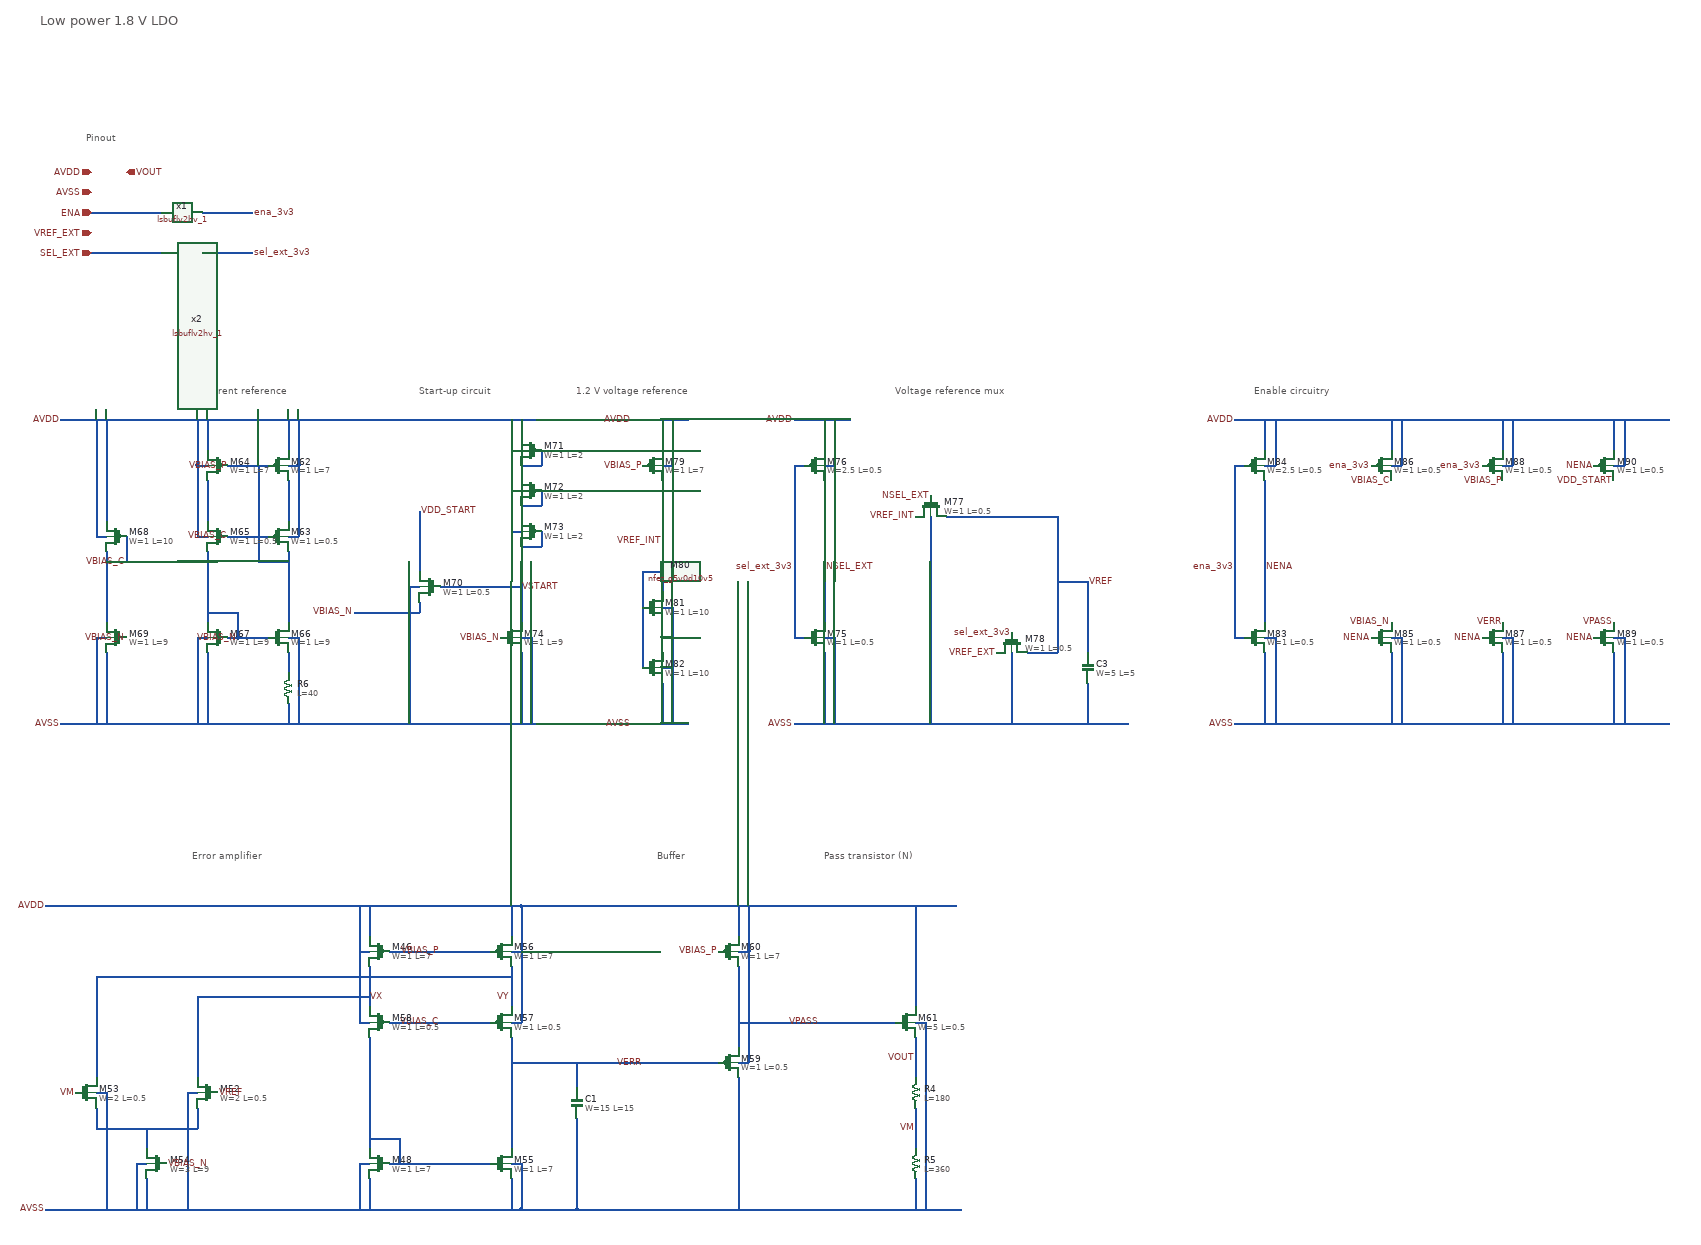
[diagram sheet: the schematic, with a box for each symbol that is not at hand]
v {xschem version=3.4.5 file_version=1.2
}
G {}
K {}
V {}
S {}
E {}
T {Low power 1.8 V LDO} 540 -2520 0 0 0.8 0.8 {}
T {Error amplifier} 840 -870 0 0 0.5 0.5 {}
T {Enable circuitry} 2940 -1790 0 0 0.5 0.5 {}
T {Pinout} 630 -2290 0 0 0.5 0.5 {}
T {Pass transistor (N)} 2090 -870 0 0 0.5 0.5 {}
T {Buffer} 1760 -870 0 0 0.5 0.5 {}
T {1.2 V voltage reference} 1600 -1790 0 0 0.5 0.5 {}
T {Current reference} 860 -1790 0 0 0.5 0.5 {}
T {Start-up circuit} 1290 -1790 0 0 0.5 0.5 {}
T {Voltage reference mux} 2230 -1790 0 0 0.5 0.5 {}
N 1190 -220 1190 -160 {
lab=AVSS}
N 1170 -530 1190 -530 {
lab=AVDD}
N 1170 -250 1190 -250 {
lab=AVSS}
N 650 -360 650 -320 {
lab=#net1}
N 650 -320 850 -320 {
lab=#net1}
N 850 -360 850 -320 {
lab=#net1}
N 750 -320 750 -280 {
lab=#net1}
N 750 -220 750 -160 {
lab=AVSS}
N 730 -250 750 -250 {
lab=AVSS}
N 730 -250 730 -160 {
lab=AVSS}
N 830 -390 850 -390 {
lab=AVSS}
N 830 -390 830 -160 {
lab=AVSS}
N 650 -390 670 -390 {
lab=AVSS}
N 670 -390 670 -160 {
lab=AVSS}
N 1190 -640 1190 -560 {
lab=VX}
N 1190 -760 1190 -700 {
lab=AVDD}
N 1170 -670 1190 -670 {
lab=AVDD}
N 1170 -760 1170 -530 {
lab=AVDD}
N 1470 -220 1470 -160 {
lab=AVSS}
N 1470 -530 1490 -530 {
lab=AVDD}
N 1470 -250 1490 -250 {
lab=AVSS}
N 1470 -640 1470 -560 {
lab=VY}
N 1470 -760 1470 -700 {
lab=AVDD}
N 1470 -670 1490 -670 {
lab=AVDD}
N 1490 -760 1490 -530 {
lab=AVDD}
N 1230 -670 1430 -670 {
lab=VBIAS_P}
N 1230 -530 1430 -530 {
lab=VBIAS_C}
N 1230 -250 1430 -250 {
lab=#net2}
N 1250 -300 1250 -250 {
lab=#net2}
N 1190 -300 1250 -300 {
lab=#net2}
N 850 -580 850 -420 {
lab=VX}
N 850 -580 1190 -580 {
lab=VX}
N 650 -620 650 -420 {
lab=VY}
N 650 -620 1470 -620 {
lab=VY}
N 550 -160 1490 -160 {
lab=AVSS}
N 550 -760 1490 -760 {
lab=AVDD}
N 1190 -500 1190 -280 {
lab=#net2}
N 1470 -500 1470 -280 {
lab=VERR}
N 1490 -250 1490 -160 {
lab=AVSS}
N 1170 -250 1170 -160 {
lab=AVSS}
N 1920 -640 1920 -480 {
lab=VPASS}
N 2270 -500 2270 -420 {
lab=VOUT}
N 2270 -360 2270 -280 {
lab=VM}
N 2270 -220 2270 -160 {
lab=AVSS}
N 2270 -530 2290 -530 {
lab=AVSS}
N 2290 -530 2290 -160 {
lab=AVSS}
N 1600 -340 1600 -160 {
lab=AVSS}
N 1490 -160 1600 -160 {
lab=AVSS}
N 580 -1120 1520 -1120 {
lab=AVSS}
N 580 -1720 1520 -1720 {
lab=AVDD}
N 1030 -1720 1030 -1660 {
lab=AVDD}
N 1030 -1630 1050 -1630 {
lab=AVDD}
N 1050 -1720 1050 -1630 {
lab=AVDD}
N 1030 -1600 1030 -1520 {
lab=#net3}
N 870 -1720 870 -1660 {
lab=AVDD}
N 850 -1630 870 -1630 {
lab=AVDD}
N 850 -1720 850 -1630 {
lab=AVDD}
N 870 -1600 870 -1520 {
lab=#net4}
N 910 -1630 990 -1630 {
lab=VBIAS_P}
N 910 -1490 990 -1490 {
lab=VBIAS_C}
N 1030 -1490 1050 -1490 {
lab=AVDD}
N 1050 -1630 1050 -1490 {
lab=AVDD}
N 850 -1490 870 -1490 {
lab=AVDD}
N 850 -1630 850 -1490 {
lab=AVDD}
N 1030 -1260 1030 -1220 {
lab=#net5}
N 870 -1260 870 -1120 {
lab=AVSS}
N 1030 -1290 1050 -1290 {
lab=AVSS}
N 1050 -1290 1050 -1120 {
lab=AVSS}
N 850 -1290 870 -1290 {
lab=AVSS}
N 850 -1290 850 -1120 {
lab=AVSS}
N 970 -1630 970 -1440 {
lab=VBIAS_P}
N 970 -1440 1030 -1440 {
lab=VBIAS_P}
N 930 -1340 930 -1290 {
lab=VBIAS_N}
N 870 -1340 930 -1340 {
lab=VBIAS_N}
N 650 -1490 670 -1490 {
lab=AVDD}
N 670 -1460 670 -1320 {
lab=VBIAS_C}
N 650 -1720 650 -1490 {
lab=AVDD}
N 670 -1260 670 -1120 {
lab=AVSS}
N 650 -1290 670 -1290 {
lab=AVSS}
N 650 -1290 650 -1120 {
lab=AVSS}
N 670 -1720 670 -1520 {
lab=AVDD}
N 710 -1490 710 -1440 {
lab=VBIAS_C}
N 670 -1440 710 -1440 {
lab=VBIAS_C}
N 870 -1460 870 -1320 {
lab=VBIAS_N}
N 1030 -1460 1030 -1320 {
lab=VBIAS_P}
N 910 -1290 930 -1290 {
lab=VBIAS_N}
N 1290 -1360 1290 -1340 {
lab=VBIAS_N}
N 1270 -1390 1290 -1390 {
lab=AVSS}
N 1270 -1390 1270 -1120 {
lab=AVSS}
N 1490 -1470 1490 -1320 {
lab=VSTART}
N 1490 -1550 1490 -1530 {
lab=#net6}
N 1490 -1630 1490 -1610 {
lab=#net7}
N 1490 -1720 1490 -1690 {
lab=AVDD}
N 1470 -1500 1490 -1500 {
lab=AVDD}
N 1470 -1720 1470 -1500 {
lab=AVDD}
N 1470 -1660 1500 -1660 {
lab=AVDD}
N 1470 -1580 1490 -1580 {
lab=AVDD}
N 1490 -1470 1530 -1470 {
lab=VSTART}
N 1530 -1500 1530 -1470 {
lab=VSTART}
N 1490 -1550 1530 -1550 {
lab=#net6}
N 1530 -1580 1530 -1550 {
lab=#net6}
N 1490 -1630 1530 -1630 {
lab=#net7}
N 1530 -1660 1530 -1630 {
lab=#net7}
N 1330 -1390 1490 -1390 {
lab=VSTART}
N 1490 -1290 1510 -1290 {
lab=AVSS}
N 1510 -1290 1510 -1120 {
lab=AVSS}
N 2090 -1600 2090 -1320 {
lab=NSEL_EXT}
N 2030 -1630 2050 -1630 {
lab=sel_ext_3v3}
N 2030 -1630 2030 -1290 {
lab=sel_ext_3v3}
N 2030 -1290 2050 -1290 {
lab=sel_ext_3v3}
N 2090 -1260 2090 -1120 {
lab=AVSS}
N 2090 -1720 2090 -1660 {
lab=AVDD}
N 2090 -1630 2110 -1630 {
lab=AVDD}
N 2110 -1720 2110 -1630 {
lab=AVDD}
N 2090 -1290 2110 -1290 {
lab=AVSS}
N 2110 -1290 2110 -1120 {
lab=AVSS}
N 2030 -1720 2140 -1720 {
lab=AVDD}
N 2030 -1120 2130 -1120 {
lab=AVSS}
N 2330 -1530 2550 -1530 {
lab=VREF}
N 2550 -1530 2550 -1260 {
lab=VREF}
N 2490 -1260 2550 -1260 {
lab=VREF}
N 2610 -1400 2610 -1260 {
lab=VREF}
N 2550 -1400 2610 -1400 {
lab=VREF}
N 1490 -760 2350 -760 {
lab=AVDD}
N 1920 -760 1920 -700 {
lab=AVDD}
N 1920 -670 1940 -670 {
lab=AVDD}
N 1940 -760 1940 -670 {
lab=AVDD}
N 1920 -450 1940 -450 {
lab=AVDD}
N 1940 -670 1940 -450 {
lab=AVDD}
N 2270 -760 2270 -560 {
lab=AVDD}
N 1920 -530 2230 -530 {
lab=VPASS}
N 1600 -160 2360 -160 {
lab=AVSS}
N 1920 -420 1920 -160 {
lab=AVSS}
N 1470 -450 1880 -450 {
lab=VERR}
N 1600 -450 1600 -400 {
lab=VERR}
N 2130 -1120 2690 -1120 {
lab=AVSS}
N 2610 -1200 2610 -1120 {
lab=AVSS}
N 2460 -1260 2460 -1120 {
lab=AVSS}
N 2300 -1530 2300 -1120 {
lab=AVSS}
N 930 -1290 990 -1290 {
lab=VBIAS_N}
N 1030 -1160 1030 -1120 {
lab=AVSS}
N 1490 -1260 1490 -1120 {
lab=AVSS}
N 1160 -1340 1290 -1340 {
lab=VBIAS_N}
N 1770 -1200 1770 -1120 {
lab=AVSS}
N 1770 -1350 1790 -1350 {
lab=AVSS}
N 1790 -1350 1790 -1120 {
lab=AVSS}
N 1770 -1290 1790 -1290 {
lab=AVSS}
N 1770 -1230 1790 -1230 {
lab=AVSS}
N 1730 -1420 1730 -1230 {
lab=VREF_INT}
N 1730 -1420 1770 -1420 {
lab=VREF_INT}
N 1770 -1600 1770 -1380 {
lab=VREF_INT}
N 1770 -1630 1790 -1630 {
lab=AVDD}
N 1790 -1720 1790 -1630 {
lab=AVDD}
N 1770 -1720 1770 -1660 {
lab=AVDD}
N 1710 -1720 1820 -1720 {
lab=AVDD}
N 1710 -1120 1820 -1120 {
lab=AVSS}
N 2960 -1600 2960 -1320 {
lab=NENA}
N 2900 -1630 2920 -1630 {
lab=ena_3v3}
N 2900 -1630 2900 -1290 {
lab=ena_3v3}
N 2900 -1290 2920 -1290 {
lab=ena_3v3}
N 2960 -1260 2960 -1120 {
lab=AVSS}
N 2960 -1720 2960 -1660 {
lab=AVDD}
N 2960 -1630 2980 -1630 {
lab=AVDD}
N 2980 -1720 2980 -1630 {
lab=AVDD}
N 2960 -1290 2980 -1290 {
lab=AVSS}
N 2980 -1290 2980 -1120 {
lab=AVSS}
N 2900 -1720 3010 -1720 {
lab=AVDD}
N 3210 -1720 3210 -1660 {
lab=AVDD}
N 3210 -1630 3230 -1630 {
lab=AVDD}
N 3230 -1720 3230 -1630 {
lab=AVDD}
N 3210 -1260 3210 -1120 {
lab=AVSS}
N 3210 -1290 3230 -1290 {
lab=AVSS}
N 3230 -1290 3230 -1120 {
lab=AVSS}
N 3430 -1720 3430 -1660 {
lab=AVDD}
N 3430 -1630 3450 -1630 {
lab=AVDD}
N 3450 -1720 3450 -1630 {
lab=AVDD}
N 3430 -1260 3430 -1120 {
lab=AVSS}
N 3430 -1290 3450 -1290 {
lab=AVSS}
N 3450 -1290 3450 -1120 {
lab=AVSS}
N 3650 -1720 3650 -1660 {
lab=AVDD}
N 3650 -1630 3670 -1630 {
lab=AVDD}
N 3670 -1720 3670 -1630 {
lab=AVDD}
N 3650 -1260 3650 -1120 {
lab=AVSS}
N 3650 -1290 3670 -1290 {
lab=AVSS}
N 3670 -1290 3670 -1120 {
lab=AVSS}
N 1290 -1540 1290 -1420 {
lab=VDD_START}
N 3010 -1720 3760 -1720 {
lab=AVDD}
N 3010 -1120 3760 -1120 {
lab=AVSS}
N 2900 -1120 3010 -1120 {
lab=AVSS}
N 640 -2130 780 -2130 {
lab=ENA}
N 640 -2050 780 -2050 {
lab=SEL_EXT}
N 860 -2130 960 -2130 {
lab=ena_3v3}
N 860 -2050 960 -2050 {
lab=sel_ext_3v3}
C {devices/ipin.sym} 640 -2130 0 0 {name=p49 lab=ENA}
C {devices/ipin.sym} 640 -2210 0 0 {name=p35 lab=AVDD}
C {devices/ipin.sym} 640 -2170 0 0 {name=p36 lab=AVSS}
C {devices/opin.sym} 710 -2210 0 0 {name=p39 lab=VOUT}
C {devices/ipin.sym} 640 -2050 0 0 {name=p72 lab=SEL_EXT}
C {devices/ipin.sym} 640 -2090 0 0 {name=p73 lab=VREF_EXT}
C {sky130_fd_pr/pfet_g5v0d10v5.sym} 1210 -670 0 1 {name=M46
W=1
L=7
nf=1
mult=1
ad="'int((nf+1)/2) * W/nf * 0.29'" 
pd="'2*int((nf+1)/2) * (W/nf + 0.29)'"
as="'int((nf+2)/2) * W/nf * 0.29'" 
ps="'2*int((nf+2)/2) * (W/nf + 0.29)'"
nrd="'0.29 / W'" nrs="'0.29 / W'"
sa=0 sb=0 sd=0
model=pfet_g5v0d10v5
spiceprefix=X
}
C {sky130_fd_pr/nfet_g5v0d10v5.sym} 1210 -250 0 1 {name=M48
W=1
L=7
nf=1
mult=1
ad="'int((nf+1)/2) * W/nf * 0.29'" 
pd="'2*int((nf+1)/2) * (W/nf + 0.29)'"
as="'int((nf+2)/2) * W/nf * 0.29'" 
ps="'2*int((nf+2)/2) * (W/nf + 0.29)'"
nrd="'0.29 / W'" nrs="'0.29 / W'"
sa=0 sb=0 sd=0
model=nfet_g5v0d10v5
spiceprefix=X
}
C {devices/lab_pin.sym} 550 -760 0 0 {name=p3 sig_type=std_logic lab=AVDD}
C {devices/lab_pin.sym} 550 -160 0 0 {name=p4 sig_type=std_logic lab=AVSS}
C {sky130_fd_pr/nfet_g5v0d10v5.sym} 870 -390 0 1 {name=M52
W=2
L=0.5
nf=1
mult=1
ad="'int((nf+1)/2) * W/nf * 0.29'" 
pd="'2*int((nf+1)/2) * (W/nf + 0.29)'"
as="'int((nf+2)/2) * W/nf * 0.29'" 
ps="'2*int((nf+2)/2) * (W/nf + 0.29)'"
nrd="'0.29 / W'" nrs="'0.29 / W'"
sa=0 sb=0 sd=0
model=nfet_g5v0d10v5
spiceprefix=X
}
C {sky130_fd_pr/nfet_g5v0d10v5.sym} 630 -390 0 0 {name=M53
W=2
L=0.5
nf=1
mult=1
ad="'int((nf+1)/2) * W/nf * 0.29'" 
pd="'2*int((nf+1)/2) * (W/nf + 0.29)'"
as="'int((nf+2)/2) * W/nf * 0.29'" 
ps="'2*int((nf+2)/2) * (W/nf + 0.29)'"
nrd="'0.29 / W'" nrs="'0.29 / W'"
sa=0 sb=0 sd=0
model=nfet_g5v0d10v5
spiceprefix=X
}
C {sky130_fd_pr/nfet_g5v0d10v5.sym} 770 -250 0 1 {name=M54
W=3
L=9
nf=1
mult=1
ad="'int((nf+1)/2) * W/nf * 0.29'" 
pd="'2*int((nf+1)/2) * (W/nf + 0.29)'"
as="'int((nf+2)/2) * W/nf * 0.29'" 
ps="'2*int((nf+2)/2) * (W/nf + 0.29)'"
nrd="'0.29 / W'" nrs="'0.29 / W'"
sa=0 sb=0 sd=0
model=nfet_g5v0d10v5
spiceprefix=X
}
C {sky130_fd_pr/nfet_g5v0d10v5.sym} 1450 -250 0 0 {name=M55
W=1
L=7
nf=1
mult=1
ad="'int((nf+1)/2) * W/nf * 0.29'" 
pd="'2*int((nf+1)/2) * (W/nf + 0.29)'"
as="'int((nf+2)/2) * W/nf * 0.29'" 
ps="'2*int((nf+2)/2) * (W/nf + 0.29)'"
nrd="'0.29 / W'" nrs="'0.29 / W'"
sa=0 sb=0 sd=0
model=nfet_g5v0d10v5
spiceprefix=X
}
C {devices/lab_pin.sym} 610 -390 2 1 {name=p1 sig_type=std_logic lab=VM}
C {devices/lab_pin.sym} 890 -390 2 0 {name=p6 sig_type=std_logic lab=VREF}
C {devices/lab_pin.sym} 790 -250 2 0 {name=p2 sig_type=std_logic lab=VBIAS_N}
C {devices/lab_pin.sym} 1330 -670 3 0 {name=p10 sig_type=std_logic lab=VBIAS_P}
C {devices/lab_pin.sym} 1330 -530 3 0 {name=p11 sig_type=std_logic lab=VBIAS_C}
C {sky130_fd_pr/pfet_g5v0d10v5.sym} 1450 -670 0 0 {name=M56
W=1
L=7
nf=1
mult=1
ad="'int((nf+1)/2) * W/nf * 0.29'" 
pd="'2*int((nf+1)/2) * (W/nf + 0.29)'"
as="'int((nf+2)/2) * W/nf * 0.29'" 
ps="'2*int((nf+2)/2) * (W/nf + 0.29)'"
nrd="'0.29 / W'" nrs="'0.29 / W'"
sa=0 sb=0 sd=0
model=pfet_g5v0d10v5
spiceprefix=X
}
C {sky130_fd_pr/pfet_g5v0d10v5.sym} 1450 -530 0 0 {name=M57
W=1
L=0.5
nf=1
mult=1
ad="'int((nf+1)/2) * W/nf * 0.29'" 
pd="'2*int((nf+1)/2) * (W/nf + 0.29)'"
as="'int((nf+2)/2) * W/nf * 0.29'" 
ps="'2*int((nf+2)/2) * (W/nf + 0.29)'"
nrd="'0.29 / W'" nrs="'0.29 / W'"
sa=0 sb=0 sd=0
model=pfet_g5v0d10v5
spiceprefix=X
}
C {sky130_fd_pr/pfet_g5v0d10v5.sym} 1210 -530 0 1 {name=M58
W=1
L=0.5
nf=1
mult=1
ad="'int((nf+1)/2) * W/nf * 0.29'" 
pd="'2*int((nf+1)/2) * (W/nf + 0.29)'"
as="'int((nf+2)/2) * W/nf * 0.29'" 
ps="'2*int((nf+2)/2) * (W/nf + 0.29)'"
nrd="'0.29 / W'" nrs="'0.29 / W'"
sa=0 sb=0 sd=0
model=pfet_g5v0d10v5
spiceprefix=X
}
C {devices/lab_pin.sym} 1190 -580 2 0 {name=p12 sig_type=std_logic lab=VX}
C {devices/lab_pin.sym} 1470 -580 2 1 {name=p15 sig_type=std_logic lab=VY}
C {sky130_fd_pr/pfet_g5v0d10v5.sym} 1900 -450 0 0 {name=M59
W=1
L=0.5
nf=1
mult=1
ad="'int((nf+1)/2) * W/nf * 0.29'" 
pd="'2*int((nf+1)/2) * (W/nf + 0.29)'"
as="'int((nf+2)/2) * W/nf * 0.29'" 
ps="'2*int((nf+2)/2) * (W/nf + 0.29)'"
nrd="'0.29 / W'" nrs="'0.29 / W'"
sa=0 sb=0 sd=0
model=pfet_g5v0d10v5
spiceprefix=X
}
C {devices/lab_pin.sym} 1730 -450 3 0 {name=p16 sig_type=std_logic lab=VERR}
C {sky130_fd_pr/pfet_g5v0d10v5.sym} 1900 -670 0 0 {name=M60
W=1
L=7
nf=1
mult=1
ad="'int((nf+1)/2) * W/nf * 0.29'" 
pd="'2*int((nf+1)/2) * (W/nf + 0.29)'"
as="'int((nf+2)/2) * W/nf * 0.29'" 
ps="'2*int((nf+2)/2) * (W/nf + 0.29)'"
nrd="'0.29 / W'" nrs="'0.29 / W'"
sa=0 sb=0 sd=0
model=pfet_g5v0d10v5
spiceprefix=X
}
C {sky130_fd_pr/res_xhigh_po_0p35.sym} 2270 -390 0 1 {name=R4
L=180
model=res_xhigh_po_0p35
spiceprefix=X
mult=1}
C {sky130_fd_pr/res_xhigh_po_0p35.sym} 2270 -250 0 1 {name=R5
L=360
model=res_xhigh_po_0p35
spiceprefix=X
mult=1}
C {devices/lab_pin.sym} 2270 -320 0 0 {name=p17 sig_type=std_logic lab=VM}
C {devices/lab_pin.sym} 2270 -460 0 0 {name=p20 sig_type=std_logic lab=VOUT}
C {sky130_fd_pr/nfet_g5v0d10v5.sym} 2250 -530 0 0 {name=M61
W=5
L=0.5
nf=1
mult=1000
ad="'int((nf+1)/2) * W/nf * 0.29'" 
pd="'2*int((nf+1)/2) * (W/nf + 0.29)'"
as="'int((nf+2)/2) * W/nf * 0.29'" 
ps="'2*int((nf+2)/2) * (W/nf + 0.29)'"
nrd="'0.29 / W'" nrs="'0.29 / W'"
sa=0 sb=0 sd=0
model=nfet_g5v0d10v5
spiceprefix=X
}
C {sky130_fd_pr/cap_mim_m3_1.sym} 1600 -370 0 0 {name=C1 model=cap_mim_m3_1 W=15 L=15 MF=3 spiceprefix=X}
C {devices/lab_pin.sym} 580 -1120 0 0 {name=p21 sig_type=std_logic lab=AVSS}
C {devices/lab_pin.sym} 580 -1720 0 0 {name=p59 sig_type=std_logic lab=AVDD}
C {sky130_fd_pr/pfet_g5v0d10v5.sym} 1010 -1630 0 0 {name=M62
W=1
L=7
nf=1
mult=1
ad="'int((nf+1)/2) * W/nf * 0.29'" 
pd="'2*int((nf+1)/2) * (W/nf + 0.29)'"
as="'int((nf+2)/2) * W/nf * 0.29'" 
ps="'2*int((nf+2)/2) * (W/nf + 0.29)'"
nrd="'0.29 / W'" nrs="'0.29 / W'"
sa=0 sb=0 sd=0
model=pfet_g5v0d10v5
spiceprefix=X
}
C {sky130_fd_pr/pfet_g5v0d10v5.sym} 1010 -1490 0 0 {name=M63
W=1
L=0.5
nf=1
mult=1
ad="'int((nf+1)/2) * W/nf * 0.29'" 
pd="'2*int((nf+1)/2) * (W/nf + 0.29)'"
as="'int((nf+2)/2) * W/nf * 0.29'" 
ps="'2*int((nf+2)/2) * (W/nf + 0.29)'"
nrd="'0.29 / W'" nrs="'0.29 / W'"
sa=0 sb=0 sd=0
model=pfet_g5v0d10v5
spiceprefix=X
}
C {sky130_fd_pr/pfet_g5v0d10v5.sym} 890 -1630 0 1 {name=M64
W=1
L=7
nf=1
mult=1
ad="'int((nf+1)/2) * W/nf * 0.29'" 
pd="'2*int((nf+1)/2) * (W/nf + 0.29)'"
as="'int((nf+2)/2) * W/nf * 0.29'" 
ps="'2*int((nf+2)/2) * (W/nf + 0.29)'"
nrd="'0.29 / W'" nrs="'0.29 / W'"
sa=0 sb=0 sd=0
model=pfet_g5v0d10v5
spiceprefix=X
}
C {sky130_fd_pr/pfet_g5v0d10v5.sym} 890 -1490 0 1 {name=M65
W=1
L=0.5
nf=1
mult=1
ad="'int((nf+1)/2) * W/nf * 0.29'" 
pd="'2*int((nf+1)/2) * (W/nf + 0.29)'"
as="'int((nf+2)/2) * W/nf * 0.29'" 
ps="'2*int((nf+2)/2) * (W/nf + 0.29)'"
nrd="'0.29 / W'" nrs="'0.29 / W'"
sa=0 sb=0 sd=0
model=pfet_g5v0d10v5
spiceprefix=X
}
C {sky130_fd_pr/nfet_g5v0d10v5.sym} 1010 -1290 0 0 {name=M66
W=1
L=9
nf=1
mult=20
ad="'int((nf+1)/2) * W/nf * 0.29'" 
pd="'2*int((nf+1)/2) * (W/nf + 0.29)'"
as="'int((nf+2)/2) * W/nf * 0.29'" 
ps="'2*int((nf+2)/2) * (W/nf + 0.29)'"
nrd="'0.29 / W'" nrs="'0.29 / W'"
sa=0 sb=0 sd=0
model=nfet_g5v0d10v5
spiceprefix=X
}
C {sky130_fd_pr/nfet_g5v0d10v5.sym} 890 -1290 0 1 {name=M67
W=1
L=9
nf=1
mult=5
ad="'int((nf+1)/2) * W/nf * 0.29'" 
pd="'2*int((nf+1)/2) * (W/nf + 0.29)'"
as="'int((nf+2)/2) * W/nf * 0.29'" 
ps="'2*int((nf+2)/2) * (W/nf + 0.29)'"
nrd="'0.29 / W'" nrs="'0.29 / W'"
sa=0 sb=0 sd=0
model=nfet_g5v0d10v5
spiceprefix=X
}
C {sky130_fd_pr/pfet_g5v0d10v5.sym} 690 -1490 0 1 {name=M68
W=1
L=10
nf=1
mult=1
ad="'int((nf+1)/2) * W/nf * 0.29'" 
pd="'2*int((nf+1)/2) * (W/nf + 0.29)'"
as="'int((nf+2)/2) * W/nf * 0.29'" 
ps="'2*int((nf+2)/2) * (W/nf + 0.29)'"
nrd="'0.29 / W'" nrs="'0.29 / W'"
sa=0 sb=0 sd=0
model=pfet_g5v0d10v5
spiceprefix=X
}
C {sky130_fd_pr/nfet_g5v0d10v5.sym} 690 -1290 0 1 {name=M69
W=1
L=9
nf=1
mult=5
ad="'int((nf+1)/2) * W/nf * 0.29'" 
pd="'2*int((nf+1)/2) * (W/nf + 0.29)'"
as="'int((nf+2)/2) * W/nf * 0.29'" 
ps="'2*int((nf+2)/2) * (W/nf + 0.29)'"
nrd="'0.29 / W'" nrs="'0.29 / W'"
sa=0 sb=0 sd=0
model=nfet_g5v0d10v5
spiceprefix=X
}
C {devices/lab_pin.sym} 710 -1440 3 0 {name=p78 sig_type=std_logic lab=VBIAS_C}
C {devices/lab_pin.sym} 910 -1490 1 1 {name=p79 sig_type=std_logic lab=VBIAS_C}
C {devices/lab_pin.sym} 910 -1630 1 1 {name=p80 sig_type=std_logic lab=VBIAS_P}
C {devices/lab_pin.sym} 930 -1290 3 0 {name=p81 sig_type=std_logic lab=VBIAS_N}
C {sky130_fd_pr/nfet_g5v0d10v5.sym} 1310 -1390 0 1 {name=M70
W=1
L=0.5
nf=1
mult=1
ad="'int((nf+1)/2) * W/nf * 0.29'" 
pd="'2*int((nf+1)/2) * (W/nf + 0.29)'"
as="'int((nf+2)/2) * W/nf * 0.29'" 
ps="'2*int((nf+2)/2) * (W/nf + 0.29)'"
nrd="'0.29 / W'" nrs="'0.29 / W'"
sa=0 sb=0 sd=0
model=nfet_g5v0d10v5
spiceprefix=X
}
C {sky130_fd_pr/pfet_g5v0d10v5.sym} 1510 -1660 0 1 {name=M71
W=1
L=2
nf=1
mult=1
ad="'int((nf+1)/2) * W/nf * 0.29'" 
pd="'2*int((nf+1)/2) * (W/nf + 0.29)'"
as="'int((nf+2)/2) * W/nf * 0.29'" 
ps="'2*int((nf+2)/2) * (W/nf + 0.29)'"
nrd="'0.29 / W'" nrs="'0.29 / W'"
sa=0 sb=0 sd=0
model=pfet_g5v0d10v5
spiceprefix=X
}
C {sky130_fd_pr/pfet_g5v0d10v5.sym} 1510 -1580 0 1 {name=M72
W=1
L=2
nf=1
mult=1
ad="'int((nf+1)/2) * W/nf * 0.29'" 
pd="'2*int((nf+1)/2) * (W/nf + 0.29)'"
as="'int((nf+2)/2) * W/nf * 0.29'" 
ps="'2*int((nf+2)/2) * (W/nf + 0.29)'"
nrd="'0.29 / W'" nrs="'0.29 / W'"
sa=0 sb=0 sd=0
model=pfet_g5v0d10v5
spiceprefix=X
}
C {sky130_fd_pr/pfet_g5v0d10v5.sym} 1510 -1500 0 1 {name=M73
W=1
L=2
nf=1
mult=1
ad="'int((nf+1)/2) * W/nf * 0.29'" 
pd="'2*int((nf+1)/2) * (W/nf + 0.29)'"
as="'int((nf+2)/2) * W/nf * 0.29'" 
ps="'2*int((nf+2)/2) * (W/nf + 0.29)'"
nrd="'0.29 / W'" nrs="'0.29 / W'"
sa=0 sb=0 sd=0
model=pfet_g5v0d10v5
spiceprefix=X
}
C {sky130_fd_pr/nfet_g5v0d10v5.sym} 1470 -1290 0 0 {name=M74
W=1
L=9
nf=1
mult=5
ad="'int((nf+1)/2) * W/nf * 0.29'" 
pd="'2*int((nf+1)/2) * (W/nf + 0.29)'"
as="'int((nf+2)/2) * W/nf * 0.29'" 
ps="'2*int((nf+2)/2) * (W/nf + 0.29)'"
nrd="'0.29 / W'" nrs="'0.29 / W'"
sa=0 sb=0 sd=0
model=nfet_g5v0d10v5
spiceprefix=X
}
C {devices/lab_pin.sym} 1490 -1390 2 0 {name=p82 sig_type=std_logic lab=VSTART}
C {sky130_fd_pr/nfet_g5v0d10v5.sym} 2070 -1290 0 0 {name=M75
W=1
L=0.5
nf=1
mult=1
ad="'int((nf+1)/2) * W/nf * 0.29'" 
pd="'2*int((nf+1)/2) * (W/nf + 0.29)'"
as="'int((nf+2)/2) * W/nf * 0.29'" 
ps="'2*int((nf+2)/2) * (W/nf + 0.29)'"
nrd="'0.29 / W'" nrs="'0.29 / W'"
sa=0 sb=0 sd=0
model=nfet_g5v0d10v5
spiceprefix=X
}
C {sky130_fd_pr/pfet_g5v0d10v5.sym} 2070 -1630 0 0 {name=M76
W=2.5
L=0.5
nf=1
mult=1
ad="'int((nf+1)/2) * W/nf * 0.29'" 
pd="'2*int((nf+1)/2) * (W/nf + 0.29)'"
as="'int((nf+2)/2) * W/nf * 0.29'" 
ps="'2*int((nf+2)/2) * (W/nf + 0.29)'"
nrd="'0.29 / W'" nrs="'0.29 / W'"
sa=0 sb=0 sd=0
model=pfet_g5v0d10v5
spiceprefix=X
}
C {devices/lab_pin.sym} 2030 -1720 0 0 {name=p83 sig_type=std_logic lab=AVDD}
C {devices/lab_pin.sym} 2030 -1120 0 0 {name=p84 sig_type=std_logic lab=AVSS}
C {devices/lab_pin.sym} 2030 -1430 0 0 {name=p85 sig_type=std_logic lab=sel_ext_3v3}
C {devices/lab_pin.sym} 2090 -1430 0 1 {name=p86 sig_type=std_logic lab=NSEL_EXT}
C {sky130_fd_pr/nfet_g5v0d10v5.sym} 2300 -1550 1 0 {name=M77
W=1
L=0.5
nf=1
mult=1
ad="'int((nf+1)/2) * W/nf * 0.29'" 
pd="'2*int((nf+1)/2) * (W/nf + 0.29)'"
as="'int((nf+2)/2) * W/nf * 0.29'" 
ps="'2*int((nf+2)/2) * (W/nf + 0.29)'"
nrd="'0.29 / W'" nrs="'0.29 / W'"
sa=0 sb=0 sd=0
model=nfet_g5v0d10v5
spiceprefix=X
}
C {sky130_fd_pr/nfet_g5v0d10v5.sym} 2460 -1280 1 0 {name=M78
W=1
L=0.5
nf=1
mult=1
ad="'int((nf+1)/2) * W/nf * 0.29'" 
pd="'2*int((nf+1)/2) * (W/nf + 0.29)'"
as="'int((nf+2)/2) * W/nf * 0.29'" 
ps="'2*int((nf+2)/2) * (W/nf + 0.29)'"
nrd="'0.29 / W'" nrs="'0.29 / W'"
sa=0 sb=0 sd=0
model=nfet_g5v0d10v5
spiceprefix=X
}
C {devices/lab_pin.sym} 2460 -1300 0 0 {name=p87 sig_type=std_logic lab=sel_ext_3v3}
C {devices/lab_pin.sym} 2270 -1530 0 0 {name=p88 sig_type=std_logic lab=VREF_INT}
C {devices/lab_pin.sym} 2430 -1260 0 0 {name=p89 sig_type=std_logic lab=VREF_EXT}
C {devices/lab_pin.sym} 2610 -1400 0 1 {name=p90 sig_type=std_logic lab=VREF}
C {devices/lab_pin.sym} 2300 -1570 0 0 {name=p91 sig_type=std_logic lab=NSEL_EXT}
C {sky130_fd_pr/cap_mim_m3_1.sym} 2610 -1230 0 0 {name=C3 model=cap_mim_m3_1 W=5 L=5 MF=1 spiceprefix=X}
C {devices/lab_pin.sym} 2080 -530 3 0 {name=p92 sig_type=std_logic lab=VPASS}
C {devices/lab_pin.sym} 710 -1290 3 0 {name=p93 sig_type=std_logic lab=VBIAS_N}
C {devices/lab_pin.sym} 1450 -1290 3 0 {name=p94 sig_type=std_logic lab=VBIAS_N}
C {devices/lab_pin.sym} 1880 -670 3 0 {name=p95 sig_type=std_logic lab=VBIAS_P}
C {sky130_fd_pr/res_xhigh_po_0p35.sym} 1030 -1190 0 1 {name=R6
L=40
model=res_xhigh_po_0p35
spiceprefix=X
mult=1}
C {devices/lab_pin.sym} 1160 -1340 3 0 {name=p96 sig_type=std_logic lab=VBIAS_N}
C {sky130_fd_pr/pfet_g5v0d10v5.sym} 1750 -1630 0 0 {name=M79
W=1
L=7
nf=1
mult=1
ad="'int((nf+1)/2) * W/nf * 0.29'" 
pd="'2*int((nf+1)/2) * (W/nf + 0.29)'"
as="'int((nf+2)/2) * W/nf * 0.29'" 
ps="'2*int((nf+2)/2) * (W/nf + 0.29)'"
nrd="'0.29 / W'" nrs="'0.29 / W'"
sa=0 sb=0 sd=0
model=pfet_g5v0d10v5
spiceprefix=X
}
C {sky130_fd_pr/nfet_g5v0d10v5.sym} 1750 -1290 0 0 {name=M80
W=1
L=10
nf=1
mult=1
ad="'int((nf+1)/2) * W/nf * 0.29'" 
pd="'2*int((nf+1)/2) * (W/nf + 0.29)'"
as="'int((nf+2)/2) * W/nf * 0.29'" 
ps="'2*int((nf+2)/2) * (W/nf + 0.29)'"
nrd="'0.29 / W'" nrs="'0.29 / W'"
sa=0 sb=0 sd=0
model=nfet_g5v0d10v5
spiceprefix=X
}
C {sky130_fd_pr/nfet_g5v0d10v5.sym} 1750 -1350 0 0 {name=M81
W=1
L=10
nf=1
mult=1
ad="'int((nf+1)/2) * W/nf * 0.29'" 
pd="'2*int((nf+1)/2) * (W/nf + 0.29)'"
as="'int((nf+2)/2) * W/nf * 0.29'" 
ps="'2*int((nf+2)/2) * (W/nf + 0.29)'"
nrd="'0.29 / W'" nrs="'0.29 / W'"
sa=0 sb=0 sd=0
model=nfet_g5v0d10v5
spiceprefix=X
}
C {sky130_fd_pr/nfet_g5v0d10v5.sym} 1750 -1230 0 0 {name=M82
W=1
L=10
nf=1
mult=1
ad="'int((nf+1)/2) * W/nf * 0.29'" 
pd="'2*int((nf+1)/2) * (W/nf + 0.29)'"
as="'int((nf+2)/2) * W/nf * 0.29'" 
ps="'2*int((nf+2)/2) * (W/nf + 0.29)'"
nrd="'0.29 / W'" nrs="'0.29 / W'"
sa=0 sb=0 sd=0
model=nfet_g5v0d10v5
spiceprefix=X
}
C {devices/lab_pin.sym} 1710 -1120 0 0 {name=p97 sig_type=std_logic lab=AVSS}
C {devices/lab_pin.sym} 1710 -1720 0 0 {name=p98 sig_type=std_logic lab=AVDD}
C {devices/lab_pin.sym} 1730 -1630 1 1 {name=p99 sig_type=std_logic lab=VBIAS_P}
C {devices/lab_pin.sym} 1770 -1480 0 0 {name=p100 sig_type=std_logic lab=VREF_INT}
C {sky130_fd_pr/nfet_g5v0d10v5.sym} 2940 -1290 0 0 {name=M83
W=1
L=0.5
nf=1
mult=1
ad="'int((nf+1)/2) * W/nf * 0.29'" 
pd="'2*int((nf+1)/2) * (W/nf + 0.29)'"
as="'int((nf+2)/2) * W/nf * 0.29'" 
ps="'2*int((nf+2)/2) * (W/nf + 0.29)'"
nrd="'0.29 / W'" nrs="'0.29 / W'"
sa=0 sb=0 sd=0
model=nfet_g5v0d10v5
spiceprefix=X
}
C {sky130_fd_pr/pfet_g5v0d10v5.sym} 2940 -1630 0 0 {name=M84
W=2.5
L=0.5
nf=1
mult=1
ad="'int((nf+1)/2) * W/nf * 0.29'" 
pd="'2*int((nf+1)/2) * (W/nf + 0.29)'"
as="'int((nf+2)/2) * W/nf * 0.29'" 
ps="'2*int((nf+2)/2) * (W/nf + 0.29)'"
nrd="'0.29 / W'" nrs="'0.29 / W'"
sa=0 sb=0 sd=0
model=pfet_g5v0d10v5
spiceprefix=X
}
C {devices/lab_pin.sym} 2900 -1720 0 0 {name=p101 sig_type=std_logic lab=AVDD}
C {devices/lab_pin.sym} 2900 -1120 0 0 {name=p102 sig_type=std_logic lab=AVSS}
C {devices/lab_pin.sym} 2900 -1430 0 0 {name=p103 sig_type=std_logic lab=ena_3v3}
C {devices/lab_pin.sym} 2960 -1430 0 1 {name=p104 sig_type=std_logic lab=NENA}
C {sky130_fd_pr/nfet_g5v0d10v5.sym} 3190 -1290 0 0 {name=M85
W=1
L=0.5
nf=1
mult=1
ad="'int((nf+1)/2) * W/nf * 0.29'" 
pd="'2*int((nf+1)/2) * (W/nf + 0.29)'"
as="'int((nf+2)/2) * W/nf * 0.29'" 
ps="'2*int((nf+2)/2) * (W/nf + 0.29)'"
nrd="'0.29 / W'" nrs="'0.29 / W'"
sa=0 sb=0 sd=0
model=nfet_g5v0d10v5
spiceprefix=X
}
C {sky130_fd_pr/pfet_g5v0d10v5.sym} 3190 -1630 0 0 {name=M86
W=1
L=0.5
nf=1
mult=1
ad="'int((nf+1)/2) * W/nf * 0.29'" 
pd="'2*int((nf+1)/2) * (W/nf + 0.29)'"
as="'int((nf+2)/2) * W/nf * 0.29'" 
ps="'2*int((nf+2)/2) * (W/nf + 0.29)'"
nrd="'0.29 / W'" nrs="'0.29 / W'"
sa=0 sb=0 sd=0
model=pfet_g5v0d10v5
spiceprefix=X
}
C {devices/lab_pin.sym} 3170 -1290 0 0 {name=p105 sig_type=std_logic lab=NENA}
C {devices/lab_pin.sym} 3210 -1320 1 0 {name=p106 sig_type=std_logic lab=VBIAS_N}
C {devices/lab_pin.sym} 3210 -1600 3 0 {name=p108 sig_type=std_logic lab=VBIAS_C}
C {sky130_fd_pr/nfet_g5v0d10v5.sym} 3410 -1290 0 0 {name=M87
W=1
L=0.5
nf=1
mult=1
ad="'int((nf+1)/2) * W/nf * 0.29'" 
pd="'2*int((nf+1)/2) * (W/nf + 0.29)'"
as="'int((nf+2)/2) * W/nf * 0.29'" 
ps="'2*int((nf+2)/2) * (W/nf + 0.29)'"
nrd="'0.29 / W'" nrs="'0.29 / W'"
sa=0 sb=0 sd=0
model=nfet_g5v0d10v5
spiceprefix=X
}
C {sky130_fd_pr/pfet_g5v0d10v5.sym} 3410 -1630 0 0 {name=M88
W=1
L=0.5
nf=1
mult=1
ad="'int((nf+1)/2) * W/nf * 0.29'" 
pd="'2*int((nf+1)/2) * (W/nf + 0.29)'"
as="'int((nf+2)/2) * W/nf * 0.29'" 
ps="'2*int((nf+2)/2) * (W/nf + 0.29)'"
nrd="'0.29 / W'" nrs="'0.29 / W'"
sa=0 sb=0 sd=0
model=pfet_g5v0d10v5
spiceprefix=X
}
C {devices/lab_pin.sym} 3390 -1290 0 0 {name=p109 sig_type=std_logic lab=NENA}
C {devices/lab_pin.sym} 3430 -1320 1 0 {name=p110 sig_type=std_logic lab=VERR}
C {devices/lab_pin.sym} 3430 -1600 3 0 {name=p112 sig_type=std_logic lab=VBIAS_P}
C {sky130_fd_pr/nfet_g5v0d10v5.sym} 3630 -1290 0 0 {name=M89
W=1
L=0.5
nf=1
mult=1
ad="'int((nf+1)/2) * W/nf * 0.29'" 
pd="'2*int((nf+1)/2) * (W/nf + 0.29)'"
as="'int((nf+2)/2) * W/nf * 0.29'" 
ps="'2*int((nf+2)/2) * (W/nf + 0.29)'"
nrd="'0.29 / W'" nrs="'0.29 / W'"
sa=0 sb=0 sd=0
model=nfet_g5v0d10v5
spiceprefix=X
}
C {sky130_fd_pr/pfet_g5v0d10v5.sym} 3630 -1630 0 0 {name=M90
W=1
L=0.5
nf=1
mult=1
ad="'int((nf+1)/2) * W/nf * 0.29'" 
pd="'2*int((nf+1)/2) * (W/nf + 0.29)'"
as="'int((nf+2)/2) * W/nf * 0.29'" 
ps="'2*int((nf+2)/2) * (W/nf + 0.29)'"
nrd="'0.29 / W'" nrs="'0.29 / W'"
sa=0 sb=0 sd=0
model=pfet_g5v0d10v5
spiceprefix=X
}
C {devices/lab_pin.sym} 3610 -1290 0 0 {name=p113 sig_type=std_logic lab=NENA}
C {devices/lab_pin.sym} 3650 -1320 1 0 {name=p114 sig_type=std_logic lab=VPASS}
C {devices/lab_pin.sym} 3610 -1630 0 0 {name=p115 sig_type=std_logic lab=NENA}
C {devices/lab_pin.sym} 3650 -1600 3 0 {name=p116 sig_type=std_logic lab=VDD_START}
C {devices/lab_pin.sym} 1290 -1540 2 0 {name=p117 sig_type=std_logic lab=VDD_START}
C {lsbuflv2hv_1.sym} 820 -2130 0 0 {name=x1 LVPWR=DVDD VGND=DVSS VNB=DVSS VPB=AVDD VPWR=AVDD prefix=sky130_fd_sc_hvl__ }
C {devices/lab_pin.sym} 960 -2130 0 1 {name=p8 sig_type=std_logic lab=ena_3v3}
C {devices/lab_pin.sym} 960 -2050 0 1 {name=p9 sig_type=std_logic lab=sel_ext_3v3}
C {lsbuflv2hv_1.sym} 820 -2050 0 0 {name=x2 LVPWR=DVDD VGND=DVSS VNB=DVSS VPB=AVDD VPWR=AVDD prefix=sky130_fd_sc_hvl__ }
C {devices/lab_pin.sym} 3170 -1630 0 0 {name=p13 sig_type=std_logic lab=ena_3v3}
C {devices/lab_pin.sym} 3390 -1630 0 0 {name=p14 sig_type=std_logic lab=ena_3v3}
